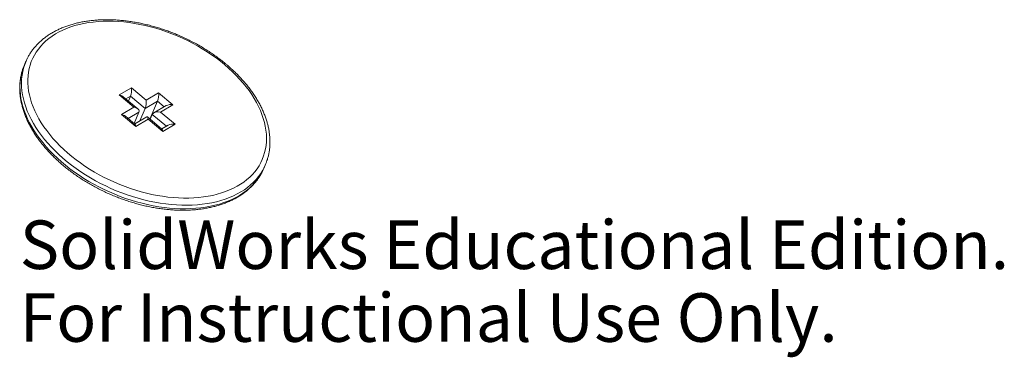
# Model space of a CAD drawing. Units: millimetres. Extents: x -12.2 to 85.9, y -23.6 to 10.
import ezdxf

# ---------------------------------------------------------------- set-up
doc = ezdxf.new("R2010")
doc.units = ezdxf.units.MM
doc.styles.add('SLDTEXTSTYLE0', font='TXT', dxfattribs={"width": 0.7})

msp = doc.modelspace()

# ---------------------------------------------------------------- linework, layer by layer
at = {"color": 7, "linetype": 'Continuous', "lineweight": 15}
for p, q in [((-11.621, 5.877), (-11.775, 5.523)), ((-2.329, 2.526), (-1.093, 3.243)), ((-1.093, 3.243), (0.364, 2.022)), ((-0.871, 1.304), (-2.329, 2.526)), ((-0.461, 1.129), (-1.918, 2.351)), ((-1.194, 2.406), (-1.66, 2.135)), ((-1.404, 1.92), (-1.194, 2.406)), ((0.263, 1.184), (-1.194, 2.406)), ((0.364, 2.022), (1.602, 2.741)), ((1.602, 2.741), (3.032, 1.543)), ((-2.11, 0.585), (-0.871, 1.304)), ((-0.278, -0.067), (0.263, 1.184)), ((1.502, 1.903), (0.263, 1.184)), ((0.733, 0.128), (1.502, 1.903)), ((2.353, 1.461), (1.114, 0.742)), ((2.162, 1.35), (1.502, 1.903)), ((3.032, 1.543), (1.793, 0.823)), ((-0.681, -0.613), (-2.11, 0.585)), ((-0.756, -0.381), (-1.699, 0.41)), ((-0.354, 0.826), (-1.442, 0.194)), ((-0.845, -0.306), (-0.354, 0.826)), ((0.428, 0.343), (-0.782, -0.359)), ((0.558, 0.106), (-0.681, -0.613)), ((1.94, -0.883), (0.482, 0.339)), ((2.015, -1.116), (0.558, 0.106)), ((0.758, 0.107), (0.969, 0.593)), ((2.381, -0.591), (0.969, 0.593)), ((1.793, 0.823), (3.25, -0.398)), ((2.571, -0.48), (1.914, -0.862)), ((3.25, -0.398), (2.015, -1.116)), ((12.082, -4.813), (12.236, -4.459))]:
    msp.add_line(p, q, dxfattribs=at)
at = {"color": 7, "linetype": 'Continuous', "lineweight": 15, "flags": 128}
for points in [[(8.181, 5.546), (7.764, 5.885), (7.332, 6.213), (6.886, 6.531), (6.428, 6.838), (5.956, 7.133), (5.474, 7.415), (4.982, 7.685), (4.48, 7.941), (3.97, 8.183), (3.453, 8.41), (2.929, 8.622), (2.401, 8.819), (1.869, 9), (1.333, 9.165), (0.797, 9.314), (0.259, 9.445), (-0.278, 9.56), (-0.814, 9.657), (-1.347, 9.736), (-1.877, 9.798), (-2.401, 9.842), (-2.92, 9.868), (-3.432, 9.876), (-3.936, 9.866), (-4.431, 9.838), (-4.916, 9.792), (-5.39, 9.728), (-5.852, 9.647), (-6.301, 9.548), (-6.736, 9.431), (-7.157, 9.298), (-7.562, 9.148), (-7.951, 8.981), (-8.322, 8.798), (-8.676, 8.599), (-9.01, 8.385), (-9.326, 8.156), (-9.622, 7.913), (-9.896, 7.655), (-10.15, 7.384), (-10.382, 7.1), (-10.592, 6.804), (-10.78, 6.496), (-10.944, 6.177), (-11.085, 5.847), (-11.203, 5.508), (-11.296, 5.16), (-11.366, 4.803), (-11.411, 4.438), (-11.433, 4.067), (-11.43, 3.69), (-11.402, 3.307), (-11.351, 2.92), (-11.275, 2.528), (-11.175, 2.134), (-11.052, 1.738), (-10.905, 1.34), (-10.735, 0.942), (-10.542, 0.544), (-10.326, 0.147), (-10.088, -0.248), (-9.829, -0.64), (-9.549, -1.029), (-9.248, -1.414), (-8.928, -1.794), (-8.588, -2.167), (-8.23, -2.535), (-7.854, -2.894), (-7.462, -3.246), (-7.053, -3.589), (-6.628, -3.922), (-6.189, -4.246), (-5.737, -4.558), (-5.272, -4.859), (-4.795, -5.148), (-4.307, -5.424), (-3.81, -5.687), (-3.304, -5.936), (-2.79, -6.17), (-2.27, -6.39), (-1.744, -6.595), (-1.213, -6.784), (-0.68, -6.957), (-0.143, -7.114), (0.394, -7.254), (0.932, -7.377), (1.468, -7.483), (2.003, -7.571), (2.534, -7.641), (3.061, -7.694), (3.583, -7.729), (4.099, -7.746), (4.607, -7.745), (5.106, -7.726), (5.596, -7.689), (6.076, -7.634), (6.544, -7.562), (7, -7.472), (7.442, -7.364), (7.87, -7.239), (8.283, -7.097), (8.68, -6.939), (9.06, -6.764), (9.423, -6.573), (9.767, -6.366), (10.093, -6.145), (10.398, -5.908), (10.683, -5.658), (10.948, -5.393), (11.191, -5.116), (11.412, -4.826), (11.611, -4.524), (11.786, -4.21), (11.939, -3.886), (12.069, -3.551), (12.174, -3.207), (12.256, -2.854), (12.314, -2.494), (12.347, -2.126), (12.356, -1.751), (12.341, -1.371), (12.301, -0.986), (12.238, -0.597), (12.15, -0.204), (12.038, 0.191), (11.903, 0.589), (11.744, 0.987), (11.563, 1.385), (11.358, 1.782), (11.132, 2.179), (10.883, 2.572), (10.614, 2.963), (10.323, 3.35), (10.013, 3.732), (9.682, 4.109), (9.333, 4.48), (8.966, 4.843), (8.582, 5.199), (8.181, 5.546)], [(-11.745, 5.565), (-11.61, 5.904), (-11.485, 6.168)], [(-11.9, 5.207), (-12.012, 4.857), (-12.1, 4.497), (-12.163, 4.128), (-12.203, 3.753), (-12.217, 3.37), (-12.207, 2.982), (-12.173, 2.588), (-12.114, 2.19), (-12.031, 1.788), (-11.924, 1.383), (-11.792, 0.977), (-11.637, 0.569), (-11.459, 0.16), (-11.257, -0.248), (-11.033, -0.654), (-10.786, -1.059), (-10.518, -1.461), (-10.229, -1.859), (-9.919, -2.253), (-9.589, -2.642), (-9.24, -3.025), (-8.872, -3.401), (-8.486, -3.77), (-8.083, -4.13), (-7.663, -4.482), (-7.229, -4.824), (-6.779, -5.155), (-6.316, -5.476), (-5.839, -5.785), (-5.351, -6.082), (-4.852, -6.367), (-4.344, -6.637), (-3.826, -6.894), (-3.3, -7.137), (-2.767, -7.365), (-2.229, -7.577), (-1.686, -7.774), (-1.139, -7.954), (-0.59, -8.118), (-0.039, -8.265), (0.512, -8.395), (1.063, -8.508), (1.612, -8.603), (2.157, -8.68), (2.699, -8.74), (3.236, -8.781), (3.767, -8.804), (4.29, -8.809), (4.805, -8.796), (5.311, -8.765), (5.807, -8.715), (6.292, -8.648), (6.764, -8.562), (7.223, -8.459), (7.669, -8.339), (8.099, -8.201), (8.513, -8.046), (8.911, -7.875), (9.292, -7.687), (9.654, -7.483), (9.998, -7.264), (10.322, -7.029), (10.626, -6.78), (10.909, -6.517), (11.17, -6.24), (11.41, -5.95), (11.628, -5.647), (11.822, -5.333), (11.941, -5.113)], [(12.093, -4.761), (11.976, -4.978), (11.781, -5.293), (11.564, -5.595), (11.324, -5.885), (11.062, -6.162), (10.779, -6.425), (10.475, -6.675), (10.152, -6.909), (9.808, -7.128), (9.446, -7.332), (9.065, -7.52), (8.667, -7.691), (8.253, -7.846), (7.822, -7.984), (7.377, -8.105), (6.918, -8.208), (6.445, -8.293), (5.961, -8.361), (5.465, -8.41), (4.959, -8.441), (4.444, -8.455), (3.92, -8.45), (3.39, -8.426), (2.853, -8.385), (2.311, -8.326), (1.765, -8.249), (1.217, -8.153), (0.666, -8.041), (0.115, -7.911), (-0.436, -7.763), (-0.985, -7.6), (-1.532, -7.419), (-2.075, -7.222), (-2.614, -7.01), (-3.146, -6.782), (-3.672, -6.54), (-4.19, -6.283), (-4.699, -6.012), (-5.198, -5.728), (-5.686, -5.431), (-6.162, -5.122), (-6.625, -4.801), (-7.075, -4.469), (-7.51, -4.127), (-7.929, -3.776), (-8.332, -3.415), (-8.718, -3.047), (-9.086, -2.67), (-9.435, -2.288), (-9.765, -1.899), (-10.075, -1.505), (-10.365, -1.106), (-10.633, -0.705), (-10.879, -0.3), (-11.103, 0.107), (-11.305, 0.515), (-11.483, 0.923), (-11.639, 1.331), (-11.77, 1.738), (-11.877, 2.143), (-11.961, 2.544), (-12.019, 2.942), (-12.054, 3.336), (-12.064, 3.725), (-12.049, 4.107), (-12.01, 4.483), (-11.946, 4.851), (-11.858, 5.211), (-11.746, 5.562), (-11.745, 5.565)], [(-11.775, 5.523), (-11.899, 5.208), (-11.9, 5.207)], [(-0.871, 1.304), (-0.743, 1.273), (-0.626, 1.23), (-0.524, 1.176), (-0.442, 1.113), (-0.382, 1.043), (-0.346, 0.971), (-0.337, 0.897), (-0.354, 0.826)], [(0.428, 0.343), (0.435, 0.347), (0.462, 0.349), (0.488, 0.334), (0.511, 0.3), (0.53, 0.25), (0.546, 0.185), (0.558, 0.106)], [(11.941, -5.113), (11.994, -5.007), (12.082, -4.813)]]:
    msp.add_lwpolyline(points, dxfattribs=at)
at = {"color": 7, "linetype": 'Continuous', "lineweight": 15}
for centre, radius, start, end in [((-2.996, 3.047), 1.912, 340.42007, 5.90056), ((-2.464, 1.64), 0.896, 52.46611, 81.31412), ((-1.538, 1.825), 1.912, 340.42007, 5.90056), ((-0.3, 2.544), 1.912, 340.42007, 5.90056), ((2.81, 0.524), 1.043, 77.70347, 115.98871), ((-2.245, -0.301), 0.896, 52.46611, 81.31412), ((1.557, 0.079), 0.781, 72.37449, 138.86167), ((-1.064, -0.609), 0.384, 359.43906, 36.57667), ((1.636, -1.11), 0.38, 359.2418, 36.77393), ((3.028, -1.417), 1.043, 77.70347, 115.98871), ((7.43, -2.377), 5.237, 332.91283, 340.13469)]:
    msp.add_arc(centre, radius, start, end, dxfattribs=at)
for points, knots in [([(8.348, 5.575), (8.278, 5.634), (8.074, 5.803), (7.726, 6.076), (7.301, 6.391), (6.864, 6.695), (6.415, 6.989), (5.955, 7.272), (5.486, 7.544), (5.008, 7.803), (4.521, 8.05), (4.027, 8.284), (3.526, 8.505), (3.02, 8.712), (2.509, 8.905), (1.994, 9.083), (1.476, 9.247), (0.956, 9.396), (0.434, 9.529), (-0.087, 9.648), (-0.608, 9.75), (-1.128, 9.836), (-1.645, 9.906), (-2.159, 9.96), (-2.668, 9.998), (-3.173, 10.019), (-3.671, 10.023), (-4.163, 10.011), (-4.647, 9.983), (-5.123, 9.937), (-5.589, 9.875), (-6.045, 9.797), (-6.49, 9.702), (-6.923, 9.591), (-7.343, 9.463), (-7.75, 9.32), (-8.142, 9.161), (-8.519, 8.986), (-8.881, 8.796), (-9.226, 8.592), (-9.554, 8.373), (-9.863, 8.141), (-10.155, 7.894), (-10.427, 7.636), (-10.68, 7.364), (-10.913, 7.082), (-11.125, 6.787), (-11.315, 6.489), (-11.424, 6.284), (-11.476, 6.184)], [0, 0, 0, 0, 0.01142, 0.033007, 0.05459, 0.076169, 0.097744, 0.119315, 0.140883, 0.162449, 0.184013, 0.205576, 0.227138, 0.248701, 0.270264, 0.291829, 0.313395, 0.334965, 0.356537, 0.378114, 0.399695, 0.421282, 0.442873, 0.464471, 0.486075, 0.507685, 0.529302, 0.550924, 0.572552, 0.594184, 0.61582, 0.637456, 0.659091, 0.680721, 0.702341, 0.723949, 0.745537, 0.7671, 0.788632, 0.810125, 0.831574, 0.852972, 0.874314, 0.895597, 0.916821, 0.937986, 0.959097, 0.980161, 1, 1, 1, 1]), ([(-11.906, 5.188), (-11.91, 5.177), (-11.958, 5.056), (-12.029, 4.815), (-12.116, 4.467), (-12.18, 4.111), (-12.223, 3.748), (-12.243, 3.379), (-12.242, 3.005), (-12.218, 2.626), (-12.172, 2.242), (-12.105, 1.856), (-12.015, 1.466), (-11.903, 1.074), (-11.77, 0.681), (-11.615, 0.288), (-11.439, -0.106), (-11.243, -0.498), (-11.026, -0.889), (-10.788, -1.277), (-10.532, -1.662), (-10.256, -2.044), (-9.962, -2.421), (-9.65, -2.793), (-9.32, -3.159), (-8.974, -3.519), (-8.612, -3.871), (-8.234, -4.216), (-7.841, -4.553), (-7.435, -4.881), (-7.015, -5.2), (-6.582, -5.509), (-6.138, -5.807), (-5.683, -6.095), (-5.217, -6.371), (-4.742, -6.635), (-4.259, -6.887), (-3.768, -7.127), (-3.27, -7.353), (-2.765, -7.565), (-2.256, -7.764), (-1.743, -7.949), (-1.226, -8.118), (-0.706, -8.273), (-0.186, -8.413), (0.336, -8.537), (0.857, -8.646), (1.378, -8.739), (1.896, -8.816), (2.411, -8.876), (2.922, -8.921), (3.429, -8.948), (3.93, -8.96), (4.425, -8.954), (4.912, -8.932), (5.391, -8.894), (5.861, -8.839), (6.322, -8.767), (6.771, -8.679), (7.209, -8.574), (7.635, -8.453), (8.047, -8.316), (8.445, -8.163), (8.829, -7.995), (9.197, -7.811), (9.549, -7.613), (9.883, -7.4), (10.201, -7.173), (10.499, -6.932), (10.78, -6.679), (11.04, -6.412), (11.282, -6.134), (11.503, -5.845), (11.702, -5.544), (11.845, -5.305), (11.914, -5.163), (11.931, -5.129)], [0, 0, 0, 0, 0.001325, 0.014818, 0.028318, 0.041832, 0.05537, 0.068936, 0.082535, 0.096171, 0.109843, 0.123552, 0.137295, 0.151069, 0.164871, 0.178697, 0.192543, 0.206405, 0.220279, 0.234163, 0.248052, 0.261945, 0.27584, 0.289735, 0.303629, 0.317521, 0.33141, 0.345296, 0.359179, 0.373059, 0.386936, 0.400809, 0.414681, 0.428549, 0.442416, 0.456281, 0.470145, 0.484007, 0.49787, 0.511732, 0.525595, 0.539458, 0.553322, 0.567188, 0.581056, 0.594927, 0.6088, 0.622676, 0.636556, 0.650439, 0.664326, 0.678218, 0.692113, 0.706012, 0.719915, 0.733821, 0.74773, 0.76164, 0.775549, 0.789456, 0.803359, 0.817254, 0.831138, 0.845008, 0.858859, 0.872687, 0.886489, 0.900259, 0.913994, 0.927693, 0.941353, 0.954975, 0.968561, 0.982114, 0.995641, 1, 1, 1, 1]), ([(12.361, -4.138), (12.39, -4.056), (12.46, -3.862), (12.544, -3.546), (12.618, -3.193), (12.669, -2.832), (12.698, -2.466), (12.706, -2.094), (12.691, -1.717), (12.655, -1.335), (12.596, -0.949), (12.515, -0.561), (12.412, -0.17), (12.288, 0.223), (12.142, 0.616), (11.974, 1.01), (11.786, 1.402), (11.577, 1.794), (11.348, 2.183), (11.099, 2.57), (10.831, 2.953), (10.545, 3.332), (10.24, 3.706), (9.917, 4.075), (9.578, 4.437), (9.222, 4.793), (8.85, 5.141), (8.556, 5.4), (8.386, 5.543), (8.348, 5.575)], [0, 0, 0, 0, 0.027673, 0.065363, 0.103087, 0.140866, 0.17872, 0.216661, 0.254701, 0.292843, 0.331087, 0.36943, 0.407865, 0.446381, 0.484969, 0.523617, 0.562313, 0.601048, 0.639812, 0.678596, 0.717393, 0.756198, 0.795004, 0.833808, 0.872608, 0.9114, 0.950185, 0.988961, 1, 1, 1, 1])]:
    msp.add_open_spline(points, degree=3, knots=knots, dxfattribs=at)

# ---------------------------------------------------------------- texts
at = {"color": 7, "linetype": 'Continuous', "char_height": 4.83362, "attachment_point": 1, "style": 'SLDTEXTSTYLE0'}
for s, insert in [('SolidWorks Educational Edition.', (-12.24, -9.977)), ('For Instructional Use Only.', (-12.24, -17.227))]:
    msp.add_mtext(s, dxfattribs=dict(at, insert=insert))

doc.saveas('drawing.dxf')
